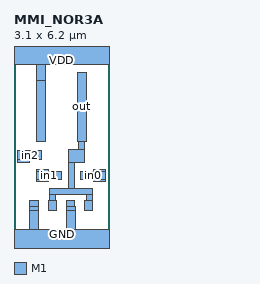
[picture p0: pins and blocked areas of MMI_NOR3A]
MACRO MMI_NOR3A
	CLASS CORE ;
	FOREIGN MMI_NOR3A 0 0 ;
	SIZE 3.1 BY 6.2 ;
	SYMMETRY X Y ;
	SITE CORE1 ;
	PIN out
		DIRECTION output ;
		USE SIGNAL ;
		PORT
			LAYER M1 ;
			RECT 2.07 3.295 2.35 5.54 ;
			LAYER M1 ;
			RECT 2.095 3.02 2.29 3.295 ;
			LAYER M1 ;
			RECT 1.765 2.6 2.29 3.02 ;
			LAYER M1 ;
			RECT 1.765 1.76 1.96 2.6 ;
			LAYER M1 ;
			RECT 1.145 1.565 2.565 1.76 ;
			LAYER M1 ;
			RECT 1.145 1.35 1.34 1.565 ;
			LAYER M1 ;
			RECT 2.37 1.35 2.565 1.565 ;
			LAYER M1 ;
			RECT 1.11 1.035 1.39 1.35 ;
			LAYER M1 ;
			RECT 2.29 1.035 2.57 1.35 ;
		END
		AntennaDiffArea 1.2359 ;
	END out
	PIN in1
		DIRECTION input ;
		USE SIGNAL ;
		PORT
			LAYER M1 ;
			RECT 0.74 2.315 1.12 2.36 ;
			LAYER M1 ;
			RECT 0.74 2.31 1.55 2.315 ;
			LAYER M1 ;
			RECT 0.74 2.03 1.565 2.31 ;
			LAYER M1 ;
			RECT 0.74 1.98 1.12 2.03 ;
		END
		AntennaGateArea 0.405 ;
	END in1
	PIN GND
		DIRECTION inout ;
		USE GROUND ;
		PORT
			LAYER M1 ;
			RECT 0.52 1.165 0.8 1.35 ;
			LAYER M1 ;
			RECT 0.51 1.035 0.8 1.165 ;
			LAYER M1 ;
			RECT 1.7 1.165 1.98 1.35 ;
			LAYER M1 ;
			RECT 1.7 1.035 2 1.165 ;
			LAYER M1 ;
			RECT 0.51 0.42 0.795 1.035 ;
			LAYER M1 ;
			RECT 1.715 0.42 2 1.035 ;
			LAYER M1 ;
			RECT 0 -0.42 3.1 0.42 ;
		END
	END GND
	PIN in2
		DIRECTION input ;
		USE SIGNAL ;
		PORT
			LAYER M1 ;
			RECT 0.12 2.695 0.9 2.98 ;
			LAYER M1 ;
			RECT 0.12 2.6 0.5 2.695 ;
		END
		AntennaGateArea 0.405 ;
	END in2
	PIN VDD
		DIRECTION inout ;
		USE POWER ;
		PORT
			LAYER M1 ;
			RECT 0 5.78 3.1 6.62 ;
			LAYER M1 ;
			RECT 0.735 5.255 1.02 5.78 ;
			LAYER M1 ;
			RECT 0.74 3.295 1.02 5.255 ;
		END
	END VDD
	PIN in0
		DIRECTION input ;
		USE SIGNAL ;
		PORT
			LAYER M1 ;
			RECT 2.6 2.315 2.98 2.36 ;
			LAYER M1 ;
			RECT 2.275 2.31 2.98 2.315 ;
			LAYER M1 ;
			RECT 2.165 2.03 2.98 2.31 ;
			LAYER M1 ;
			RECT 2.6 1.98 2.98 2.03 ;
		END
		AntennaGateArea 0.405 ;
	END in0
	OBS
	END
END MMI_NOR3A
